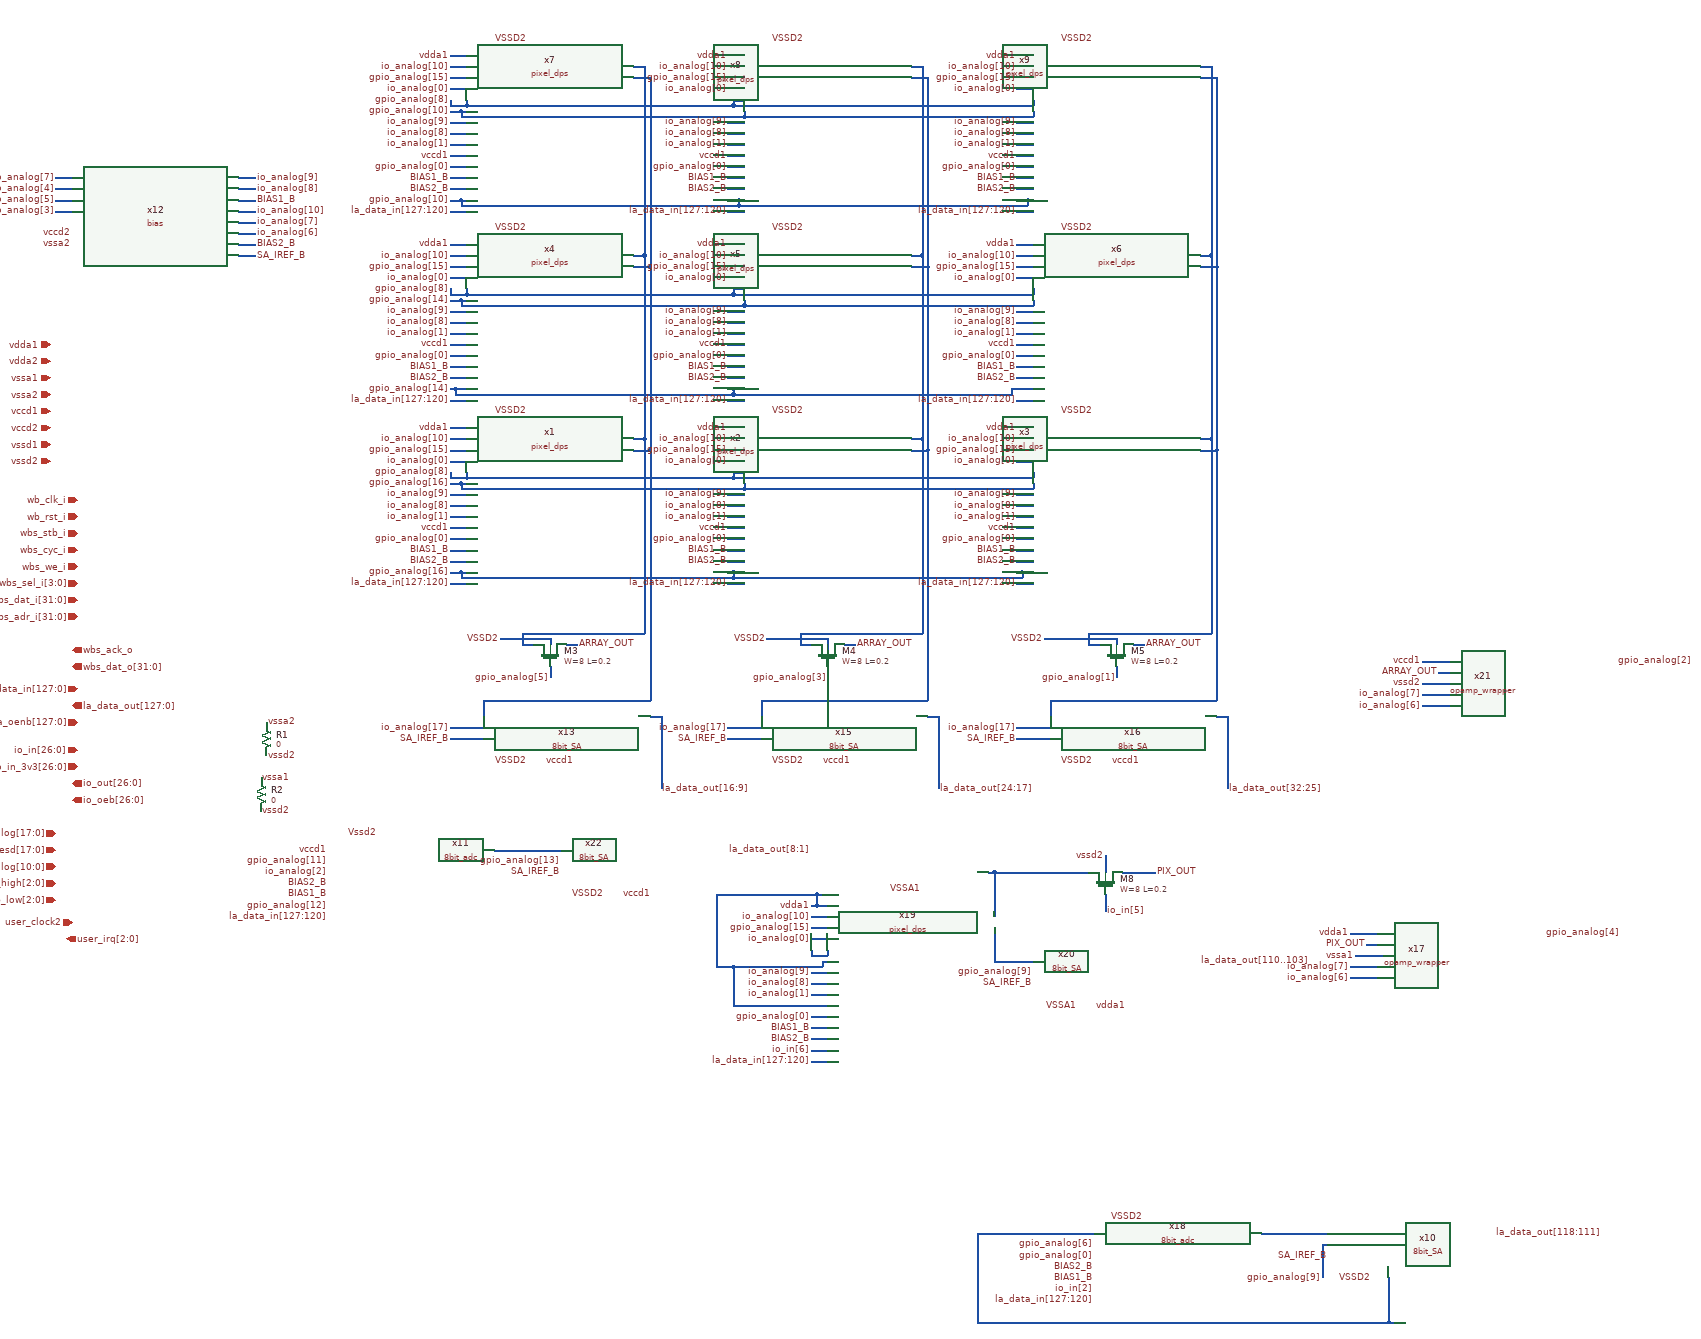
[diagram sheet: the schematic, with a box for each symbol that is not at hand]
v {xschem version=3.1.0 file_version=1.2
}
G {}
K {}
V {}
S {}
E {}
N 4290 -970 4310 -970 {
lab=#net1}
N 4310 -300 4310 50 {
lab=#net1}
N 4290 -300 4310 -300 {
lab=#net1}
N 4290 -630 4310 -630 {
lab=#net1}
N 4020 170 4320 170 {
lab=#net2}
N 4020 170 4020 200 {
lab=#net2}
N 3960 220 4020 220 {
lab=io_analog[17]}
N 3960 240 4020 240 {
lab=SA_IREF_B}
N 4320 200 4340 200 {
lab=la_data_in[16:9]}
N 4340 200 4340 330 {
lab=la_data_in[16:9]}
N 4090 50 4310 50 {
lab=#net1}
N 4090 50 4090 70 {
lab=#net1}
N 4090 70 4110 70 {
lab=#net1}
N 4170 70 4190 70 {
lab=ARRAY_OUT}
N 4140 110 4140 130 {
lab=gpio_analog[5]}
N 3580 -650 3610 -650 {
lab=BIAS2_B}
N 3580 -630 3610 -630 {
lab=SA_IREF_B}
N 3580 -670 3610 -670 {
lab=io_analog[6]}
N 3580 -730 3610 -730 {
lab=BIAS1_B}
N 3580 -710 3610 -710 {
lab=io_analog[10]}
N 3580 -690 3610 -690 {
lab=io_analog[7]}
N 3580 -750 3610 -750 {
lab=io_analog[8]}
N 3580 -770 3610 -770 {
lab=io_analog[9]}
N 3250 -770 3280 -770 {
lab=gpio_analog[7]}
N 3250 -750 3280 -750 {
lab=io_analog[4]}
N 3250 -730 3280 -730 {
lab=io_analog[5]}
N 3250 -710 3280 -710 {
lab=io_analog[3]}
N 3960 -870 3990 -870 {
lab=io_analog[9]}
N 3960 -850 3990 -850 {
lab=io_analog[8]}
N 3960 -750 3990 -750 {
lab=BIAS2_B}
N 3960 -770 3990 -770 {
lab=BIAS1_B}
N 3960 -970 3990 -970 {
lab=io_analog[10]}
N 3960 -950 3990 -950 {
lab=gpio_analog[15]}
N 3960 -930 3990 -930 {
lab=io_analog[0]}
N 3980 -890 3990 -890 {
lab=gpio_analog[10]}
N 3960 -830 3990 -830 {
lab=io_analog[1]}
N 3960 -810 3990 -810 {
lab=vccd1}
N 3960 -790 3990 -790 {
lab=gpio_analog[0]}
N 3980 -730 3990 -730 {
lab=gpio_analog[10]}
N 3960 -710 3990 -710 {
lab=la_data_in[127:120]}
N 3960 -530 3990 -530 {
lab=io_analog[9]}
N 3960 -510 3990 -510 {
lab=io_analog[8]}
N 3960 -410 3990 -410 {
lab=BIAS2_B}
N 3960 -430 3990 -430 {
lab=BIAS1_B}
N 3960 -630 3990 -630 {
lab=io_analog[10]}
N 3960 -610 3990 -610 {
lab=gpio_analog[15]}
N 3960 -590 3990 -590 {
lab=io_analog[0]}
N 3960 -490 3990 -490 {
lab=io_analog[1]}
N 3960 -470 3990 -470 {
lab=vccd1}
N 3960 -450 3990 -450 {
lab=gpio_analog[0]}
N 3970 -390 3990 -390 {
lab=gpio_analog[14]}
N 3960 -370 3990 -370 {
lab=la_data_in[127:120]}
N 3960 -200 3990 -200 {
lab=io_analog[9]}
N 3960 -180 3990 -180 {
lab=io_analog[8]}
N 3960 -80 3990 -80 {
lab=BIAS2_B}
N 3960 -100 3990 -100 {
lab=BIAS1_B}
N 3960 -300 3990 -300 {
lab=io_analog[10]}
N 3960 -280 3990 -280 {
lab=gpio_analog[15]}
N 3960 -260 3990 -260 {
lab=io_analog[0]}
N 3960 -160 3990 -160 {
lab=io_analog[1]}
N 3960 -140 3990 -140 {
lab=vccd1}
N 3960 -120 3990 -120 {
lab=gpio_analog[0]}
N 3980 -60 3990 -60 {
lab=gpio_analog[16]}
N 3960 -40 3990 -40 {
lab=la_data_in[127:120]}
N 4460 -870 4490 -870 {
lab=io_analog[9]}
N 4460 -850 4490 -850 {
lab=io_analog[8]}
N 4460 -750 4490 -750 {
lab=BIAS2_B}
N 4460 -770 4490 -770 {
lab=BIAS1_B}
N 4460 -970 4490 -970 {
lab=io_analog[10]}
N 4460 -950 4490 -950 {
lab=gpio_analog[15]}
N 4460 -930 4490 -930 {
lab=io_analog[0]}
N 4460 -830 4490 -830 {
lab=io_analog[1]}
N 4460 -810 4490 -810 {
lab=vccd1}
N 4460 -790 4490 -790 {
lab=gpio_analog[0]}
N 4480 -730 4490 -730 {
lab=gpio_analog[10]}
N 4460 -710 4490 -710 {
lab=la_data_in[127:120]}
N 4460 -530 4490 -530 {
lab=io_analog[9]}
N 4460 -510 4490 -510 {
lab=io_analog[8]}
N 4460 -410 4490 -410 {
lab=BIAS2_B}
N 4460 -430 4490 -430 {
lab=BIAS1_B}
N 4460 -630 4490 -630 {
lab=io_analog[10]}
N 4460 -610 4490 -610 {
lab=gpio_analog[15]}
N 4460 -590 4490 -590 {
lab=io_analog[0]}
N 4460 -490 4490 -490 {
lab=io_analog[1]}
N 4460 -470 4490 -470 {
lab=vccd1}
N 4460 -450 4490 -450 {
lab=gpio_analog[0]}
N 4470 -390 4490 -390 {
lab=gpio_analog[14]}
N 4460 -370 4490 -370 {
lab=la_data_in[127:120]}
N 4460 -200 4490 -200 {
lab=io_analog[9]}
N 4460 -180 4490 -180 {
lab=io_analog[8]}
N 4460 -80 4490 -80 {
lab=BIAS2_B}
N 4460 -100 4490 -100 {
lab=BIAS1_B}
N 4460 -300 4490 -300 {
lab=io_analog[10]}
N 4460 -280 4490 -280 {
lab=gpio_analog[15]}
N 4460 -260 4490 -260 {
lab=io_analog[0]}
N 4460 -160 4490 -160 {
lab=io_analog[1]}
N 4460 -140 4490 -140 {
lab=vccd1}
N 4460 -120 4490 -120 {
lab=gpio_analog[0]}
N 4470 -60 4490 -60 {
lab=gpio_analog[16]}
N 4460 -40 4490 -40 {
lab=la_data_in[127:120]}
N 4790 -970 4810 -970 {
lab=#net3}
N 4810 -300 4810 50 {
lab=#net3}
N 4790 -300 4810 -300 {
lab=#net3}
N 4790 -630 4810 -630 {
lab=#net3}
N 4980 -870 5010 -870 {
lab=io_analog[9]}
N 4980 -850 5010 -850 {
lab=io_analog[8]}
N 4980 -750 5010 -750 {
lab=BIAS2_B}
N 4980 -770 5010 -770 {
lab=BIAS1_B}
N 4980 -970 5010 -970 {
lab=io_analog[10]}
N 4980 -950 5010 -950 {
lab=gpio_analog[15]}
N 4980 -930 5010 -930 {
lab=io_analog[0]}
N 4980 -830 5010 -830 {
lab=io_analog[1]}
N 4980 -810 5010 -810 {
lab=vccd1}
N 4980 -790 5010 -790 {
lab=gpio_analog[0]}
N 5000 -730 5010 -730 {
lab=gpio_analog[10]}
N 4980 -710 5010 -710 {
lab=la_data_in[127:120]}
N 4980 -530 5010 -530 {
lab=io_analog[9]}
N 4980 -510 5010 -510 {
lab=io_analog[8]}
N 4980 -410 5010 -410 {
lab=BIAS2_B}
N 4980 -430 5010 -430 {
lab=BIAS1_B}
N 4980 -630 5010 -630 {
lab=io_analog[10]}
N 4980 -610 5010 -610 {
lab=gpio_analog[15]}
N 4980 -590 5010 -590 {
lab=io_analog[0]}
N 4980 -490 5010 -490 {
lab=io_analog[1]}
N 4980 -470 5010 -470 {
lab=vccd1}
N 4980 -450 5010 -450 {
lab=gpio_analog[0]}
N 4980 -370 5010 -370 {
lab=la_data_in[127:120]}
N 4980 -200 5010 -200 {
lab=io_analog[9]}
N 4980 -180 5010 -180 {
lab=io_analog[8]}
N 4980 -80 5010 -80 {
lab=BIAS2_B}
N 4980 -100 5010 -100 {
lab=BIAS1_B}
N 4980 -300 5010 -300 {
lab=io_analog[10]}
N 4980 -280 5010 -280 {
lab=gpio_analog[15]}
N 4980 -260 5010 -260 {
lab=io_analog[0]}
N 4980 -160 5010 -160 {
lab=io_analog[1]}
N 4980 -140 5010 -140 {
lab=vccd1}
N 4980 -120 5010 -120 {
lab=gpio_analog[0]}
N 4990 -60 5010 -60 {
lab=gpio_analog[16]}
N 4980 -40 5010 -40 {
lab=la_data_in[127:120]}
N 5310 -970 5330 -970 {
lab=#net4}
N 5330 -300 5330 50 {
lab=#net4}
N 5310 -300 5330 -300 {
lab=#net4}
N 5310 -630 5330 -630 {
lab=#net4}
N 4520 170 4820 170 {
lab=#net5}
N 4520 170 4520 200 {
lab=#net5}
N 4460 220 4520 220 {
lab=io_analog[17]}
N 4460 240 4520 240 {
lab=SA_IREF_B}
N 4820 200 4840 200 {
lab=la_data_in[24:17]}
N 4840 200 4840 330 {
lab=la_data_in[24:17]}
N 4590 50 4810 50 {
lab=#net3}
N 4590 50 4590 70 {
lab=#net3}
N 4590 70 4610 70 {
lab=#net3}
N 4670 70 4690 70 {
lab=ARRAY_OUT}
N 4640 110 4640 130 {
lab=gpio_analog[3]}
N 5040 170 5340 170 {
lab=#net6}
N 5040 170 5040 200 {
lab=#net6}
N 4980 220 5040 220 {
lab=io_analog[17]}
N 4980 240 5040 240 {
lab=SA_IREF_B}
N 5340 200 5360 200 {
lab=la_data_in[32:25]}
N 5360 200 5360 330 {
lab=la_data_in[32:25]}
N 5110 50 5330 50 {
lab=#net4}
N 5110 50 5110 70 {
lab=#net4}
N 5110 70 5130 70 {
lab=#net4}
N 5190 70 5210 70 {
lab=ARRAY_OUT}
N 5160 110 5160 130 {
lab=gpio_analog[1]}
N 4140 60 4140 70 {
lab=VSSD2}
N 4050 60 4140 60 {
lab=VSSD2}
N 4640 60 4640 80 {
lab=VSSD2}
N 4530 60 4640 60 {
lab=VSSD2}
N 5160 60 5160 70 {
lab=VSSD2}
N 5030 60 5160 60 {
lab=VSSD2}
N 4310 -630 4310 -300 {
lab=#net1}
N 4310 -970 4310 -630 {
lab=#net1}
N 4320 -610 4320 -280 {
lab=#net2}
N 4810 -630 4810 -300 {
lab=#net3}
N 4810 -970 4810 -630 {
lab=#net3}
N 4820 -610 4820 -280 {
lab=#net5}
N 5330 -630 5330 -300 {
lab=#net4}
N 5330 -970 5330 -630 {
lab=#net4}
N 5340 -610 5340 -280 {
lab=#net6}
N 4470 -910 4490 -910 {
lab=gpio_analog[8]}
N 4470 -910 4470 -900 {
lab=gpio_analog[8]}
N 3990 -900 4470 -900 {
lab=gpio_analog[8]}
N 3960 -910 3960 -900 {
lab=gpio_analog[8]}
N 3990 -910 3990 -900 {
lab=gpio_analog[8]}
N 4470 -900 5010 -900 {
lab=gpio_analog[8]}
N 5010 -910 5010 -900 {
lab=gpio_analog[8]}
N 4470 -570 4490 -570 {
lab=gpio_analog[8]}
N 4470 -570 4470 -560 {
lab=gpio_analog[8]}
N 3990 -560 4470 -560 {
lab=gpio_analog[8]}
N 3990 -570 3990 -560 {
lab=gpio_analog[8]}
N 4470 -560 5010 -560 {
lab=gpio_analog[8]}
N 5010 -570 5010 -560 {
lab=gpio_analog[8]}
N 3960 -570 3960 -560 {
lab=gpio_analog[8]}
N 4470 -240 4490 -240 {
lab=gpio_analog[8]}
N 4470 -240 4470 -230 {
lab=gpio_analog[8]}
N 3990 -230 4470 -230 {
lab=gpio_analog[8]}
N 3990 -240 3990 -230 {
lab=gpio_analog[8]}
N 4470 -230 5010 -230 {
lab=gpio_analog[8]}
N 5010 -240 5010 -230 {
lab=gpio_analog[8]}
N 3960 -240 3960 -230 {
lab=gpio_analog[8]}
N 4320 -950 4320 -610 {
lab=#net2}
N 4290 -950 4320 -950 {
lab=#net2}
N 4290 -610 4320 -610 {
lab=#net2}
N 4290 -280 4320 -280 {
lab=#net2}
N 4790 -610 4820 -610 {
lab=#net5}
N 4820 -950 4820 -610 {
lab=#net5}
N 4790 -950 4820 -950 {
lab=#net5}
N 4790 -280 4820 -280 {
lab=#net5}
N 5310 -950 5340 -950 {
lab=#net6}
N 5310 -610 5340 -610 {
lab=#net6}
N 5310 -280 5340 -280 {
lab=#net6}
N 4320 -280 4320 170 {
lab=#net2}
N 4820 -280 4820 170 {
lab=#net5}
N 5340 -280 5340 170 {
lab=#net6}
N 5340 -950 5340 -610 {
lab=#net6}
N 3960 -900 3990 -900 {
lab=gpio_analog[8]}
N 3960 -560 3990 -560 {
lab=gpio_analog[8]}
N 3960 -230 3990 -230 {
lab=gpio_analog[8]}
N 3980 -890 3980 -880 {
lab=gpio_analog[10]}
N 3980 -880 4490 -880 {
lab=gpio_analog[10]}
N 4490 -890 4490 -880 {
lab=gpio_analog[10]}
N 4490 -880 5010 -880 {
lab=gpio_analog[10]}
N 5010 -890 5010 -880 {
lab=gpio_analog[10]}
N 3960 -890 3980 -890 {
lab=gpio_analog[10]}
N 3980 -550 3990 -550 {
lab=gpio_analog[14]}
N 3980 -550 3980 -540 {
lab=gpio_analog[14]}
N 3980 -540 4490 -540 {
lab=gpio_analog[14]}
N 4490 -550 4490 -540 {
lab=gpio_analog[14]}
N 4490 -540 5010 -540 {
lab=gpio_analog[14]}
N 5010 -550 5010 -540 {
lab=gpio_analog[14]}
N 3960 -550 3980 -550 {
lab=gpio_analog[14]}
N 3980 -220 3990 -220 {
lab=gpio_analog[16]}
N 3980 -220 3980 -210 {
lab=gpio_analog[16]}
N 3980 -210 4490 -210 {
lab=gpio_analog[16]}
N 4490 -220 4490 -210 {
lab=gpio_analog[16]}
N 4490 -210 5010 -210 {
lab=gpio_analog[16]}
N 5010 -220 5010 -210 {
lab=gpio_analog[16]}
N 3960 -220 3980 -220 {
lab=gpio_analog[16]}
N 5140 520 5140 550 {
lab=io_in[5]}
N 5140 450 5140 480 {
lab=vssd2}
N 4940 480 5110 480 {
lab=#net7}
N 4940 480 4940 560 {
lab=#net7}
N 5170 480 5230 480 {
lab=PIX_OUT}
N 4940 580 4940 640 {
lab=#net8}
N 4940 640 5010 640 {
lab=#net8}
N 3960 -320 3990 -320 {
lab=vdda1}
N 3960 -650 3990 -650 {
lab=vdda1}
N 3960 -990 3990 -990 {
lab=vdda1}
N 4460 -990 4490 -990 {
lab=vdda1}
N 4980 -990 5010 -990 {
lab=vdda1}
N 4980 -650 5010 -650 {
lab=vdda1}
N 4460 -650 4490 -650 {
lab=vdda1}
N 4460 -320 4490 -320 {
lab=vdda1}
N 4980 -320 5010 -320 {
lab=vdda1}
N 4610 660 4640 660 {
lab=io_analog[9]}
N 4610 680 4640 680 {
lab=io_analog[8]}
N 4610 780 4640 780 {
lab=BIAS2_B}
N 4610 760 4640 760 {
lab=BIAS1_B}
N 4610 560 4640 560 {
lab=io_analog[10]}
N 4610 580 4640 580 {
lab=gpio_analog[15]}
N 4610 600 4640 600 {
lab=io_analog[0]}
N 4610 700 4640 700 {
lab=io_analog[1]}
N 4610 740 4640 740 {
lab=gpio_analog[0]}
N 4610 800 4640 800 {
lab=io_in[6]}
N 4610 820 4640 820 {
lab=la_data_in[127:120]}
N 4640 620 4640 630 {
lab=#net9}
N 4610 620 4610 630 {
lab=#net9}
N 4610 630 4640 630 {
lab=#net9}
N 4630 640 4640 640 {
lab=vdda1}
N 4630 640 4630 650 {
lab=vdda1}
N 4620 540 4640 540 {
lab=vdda1}
N 4040 440 4160 440 {
lab=#net10}
N 5420 1130 5540 1130 {
lab=#net11}
N 4470 650 4630 650 {
lab=vdda1}
N 5530 1150 5530 1210 {
lab=gpio_analog[9]}
N 5530 1150 5540 1150 {
lab=gpio_analog[9]}
N 4620 520 4630 520 {
lab=vdda1}
N 4930 480 4940 480 {
lab=#net7}
N 4440 520 4440 650 {
lab=vdda1}
N 4610 540 4620 540 {
lab=vdda1}
N 3980 -60 3980 -50 {
lab=gpio_analog[16]}
N 3980 -50 4470 -50 {
lab=gpio_analog[16]}
N 4470 -60 4470 -50 {
lab=gpio_analog[16]}
N 4470 -50 4990 -50 {
lab=gpio_analog[16]}
N 4990 -60 4990 -50 {
lab=gpio_analog[16]}
N 4470 720 4640 720 {
lab=vdda1}
N 4470 650 4470 720 {
lab=vdda1}
N 3970 -390 3970 -380 {
lab=gpio_analog[14]}
N 3970 -380 4470 -380 {
lab=gpio_analog[14]}
N 4470 -390 4470 -380 {
lab=gpio_analog[14]}
N 4470 -380 4970 -380 {
lab=gpio_analog[14]}
N 4970 -390 5010 -390 {
lab=gpio_analog[14]}
N 4970 -390 4970 -380 {
lab=gpio_analog[14]}
N 3980 -730 3980 -720 {
lab=gpio_analog[10]}
N 3980 -720 4480 -720 {
lab=gpio_analog[10]}
N 4480 -730 4480 -720 {
lab=gpio_analog[10]}
N 4480 -720 5000 -720 {
lab=gpio_analog[10]}
N 5000 -730 5000 -720 {
lab=gpio_analog[10]}
N 3960 -60 3980 -60 {
lab=gpio_analog[16]}
N 4460 -60 4470 -60 {
lab=gpio_analog[16]}
N 4980 -60 4990 -60 {
lab=gpio_analog[16]}
N 4440 650 4470 650 {
lab=vdda1}
N 3960 -390 3970 -390 {
lab=gpio_analog[14]}
N 4460 -390 4470 -390 {
lab=gpio_analog[14]}
N 3960 -730 3980 -730 {
lab=gpio_analog[10]}
N 4460 -730 4480 -730 {
lab=gpio_analog[10]}
N 4980 -730 5000 -730 {
lab=gpio_analog[10]}
N 4620 520 4620 540 {
lab=vdda1}
N 5650 1290 5660 1290 {
lab=#net12}
N 5650 1210 5650 1290 {
lab=#net12}
N 4910 1130 5120 1130 {
lab=#net12}
N 4440 520 4620 520 {
lab=vdda1}
N 4910 1130 4910 1290 {
lab=#net12}
N 4910 1290 5650 1290 {
lab=#net12}
N 5580 590 5630 590 {
lab=vdda1}
N 5590 630 5640 630 {
lab=vssa1}
N 5610 610 5630 610 {
lab=PIX_OUT}
N 5580 670 5630 670 {
lab=io_analog[6]}
N 5580 650 5630 650 {
lab=io_analog[7]}
N 5740 120 5760 120 {
lab=ARRAY_OUT}
N 5710 100 5760 100 {
lab=vccd1}
N 5710 140 5760 140 {
lab=vssd2}
N 5710 160 5760 160 {
lab=io_analog[7]}
N 5710 180 5760 180 {
lab=io_analog[6]}
C {devices/iopin.sym} 3240 -470 0 0 {name=p1 lab=vdda1}
C {devices/iopin.sym} 3240 -440 0 0 {name=p2 lab=vdda2}
C {devices/iopin.sym} 3240 -410 0 0 {name=p3 lab=vssa1}
C {devices/iopin.sym} 3240 -380 0 0 {name=p4 lab=vssa2}
C {devices/iopin.sym} 3240 -350 0 0 {name=p5 lab=vccd1}
C {devices/iopin.sym} 3240 -320 0 0 {name=p6 lab=vccd2}
C {devices/iopin.sym} 3240 -290 0 0 {name=p7 lab=vssd1}
C {devices/iopin.sym} 3240 -260 0 0 {name=p8 lab=vssd2}
C {devices/ipin.sym} 3290 -190 0 0 {name=p9 lab=wb_clk_i}
C {devices/ipin.sym} 3290 -160 0 0 {name=p10 lab=wb_rst_i}
C {devices/ipin.sym} 3290 -130 0 0 {name=p11 lab=wbs_stb_i}
C {devices/ipin.sym} 3290 -100 0 0 {name=p12 lab=wbs_cyc_i}
C {devices/ipin.sym} 3290 -70 0 0 {name=p13 lab=wbs_we_i}
C {devices/ipin.sym} 3290 -40 0 0 {name=p14 lab=wbs_sel_i[3:0]}
C {devices/ipin.sym} 3290 -10 0 0 {name=p15 lab=wbs_dat_i[31:0]}
C {devices/ipin.sym} 3290 20 0 0 {name=p16 lab=wbs_adr_i[31:0]}
C {devices/opin.sym} 3280 80 0 0 {name=p17 lab=wbs_ack_o}
C {devices/opin.sym} 3280 110 0 0 {name=p18 lab=wbs_dat_o[31:0]}
C {devices/ipin.sym} 3290 150 0 0 {name=p19 lab=la_data_in[127:0]}
C {devices/opin.sym} 3280 180 0 0 {name=p20 lab=la_data_out[127:0]}
C {devices/ipin.sym} 3290 260 0 0 {name=p21 lab=io_in[26:0]}
C {devices/ipin.sym} 3290 290 0 0 {name=p22 lab=io_in_3v3[26:0]}
C {devices/ipin.sym} 3280 570 0 0 {name=p23 lab=user_clock2}
C {devices/opin.sym} 3280 320 0 0 {name=p24 lab=io_out[26:0]}
C {devices/opin.sym} 3280 350 0 0 {name=p25 lab=io_oeb[26:0]}
C {devices/iopin.sym} 3250 410 0 0 {name=p26 lab=gpio_analog[17:0]}
C {devices/iopin.sym} 3250 440 0 0 {name=p27 lab=gpio_noesd[17:0]}
C {devices/iopin.sym} 3250 470 0 0 {name=p29 lab=io_analog[10:0]}
C {devices/iopin.sym} 3250 500 0 0 {name=p30 lab=io_clamp_high[2:0]}
C {devices/iopin.sym} 3250 530 0 0 {name=p31 lab=io_clamp_low[2:0]}
C {devices/opin.sym} 3270 600 0 0 {name=p32 lab=user_irq[2:0]}
C {devices/ipin.sym} 3290 210 0 0 {name=p28 lab=la_oenb[127:0]}
C {pixel_dps.sym} 4140 -180 0 0 {name=x1}
C {pixel_dps.sym} 4640 -180 0 0 {name=x2}
C {pixel_dps.sym} 4140 -510 0 0 {name=x4}
C {pixel_dps.sym} 4640 -510 0 0 {name=x5}
C {pixel_dps.sym} 4140 -850 0 0 {name=x7}
C {pixel_dps.sym} 4640 -850 0 0 {name=x8}
C {bias.sym} 3430 -700 0 0 {name=x12}
C {8bit_SA.sym} 4170 220 0 0 {name=x13}
C {sky130_fd_pr/nfet_01v8_lvt.sym} 4140 90 3 0 {name=M3
L=0.2
W=8
nf=1
mult=1
ad="'int((nf+1)/2) * W/nf * 0.29'" 
pd="'2*int((nf+1)/2) * (W/nf + 0.29)'"
as="'int((nf+2)/2) * W/nf * 0.29'" 
ps="'2*int((nf+2)/2) * (W/nf + 0.29)'"
nrd="'0.29 / W'" nrs="'0.29 / W'"
sa=0 sb=0 sd=0
model=nfet_01v8_lvt
spiceprefix=X
}
C {devices/lab_pin.sym} 3610 -630 2 0 {name=l11 sig_type=std_logic lab=SA_IREF_B}
C {devices/lab_pin.sym} 3960 240 0 0 {name=l12 sig_type=std_logic lab=SA_IREF_B}
C {devices/lab_pin.sym} 4140 130 0 0 {name=l34 sig_type=std_logic lab=gpio_analog[5]}
C {devices/lab_pin.sym} 4190 70 2 0 {name=l35 sig_type=std_logic lab=ARRAY_OUT}
C {devices/lab_pin.sym} 3610 -650 2 0 {name=l38 sig_type=std_logic lab=BIAS2_B}
C {devices/lab_pin.sym} 3610 -730 2 0 {name=l39 sig_type=std_logic lab=BIAS1_B}
C {devices/lab_pin.sym} 3610 -710 2 0 {name=l40 sig_type=std_logic lab=io_analog[10]}
C {devices/lab_pin.sym} 3610 -770 2 0 {name=l41 sig_type=std_logic lab=io_analog[9]}
C {devices/lab_pin.sym} 3610 -750 2 0 {name=l42 sig_type=std_logic lab=io_analog[8]}
C {devices/lab_pin.sym} 3250 -750 0 0 {name=l45 sig_type=std_logic lab=io_analog[4]}
C {devices/lab_pin.sym} 3960 -870 0 0 {name=l49 sig_type=std_logic lab=io_analog[9]}
C {devices/lab_pin.sym} 3960 -850 0 0 {name=l50 sig_type=std_logic lab=io_analog[8]}
C {devices/lab_pin.sym} 3960 -750 0 0 {name=l51 sig_type=std_logic lab=BIAS2_B}
C {devices/lab_pin.sym} 3960 -770 0 0 {name=l52 sig_type=std_logic lab=BIAS1_B}
C {devices/lab_pin.sym} 3960 -970 0 0 {name=l53 sig_type=std_logic lab=io_analog[10]}
C {devices/lab_pin.sym} 3960 -950 0 0 {name=l54 sig_type=std_logic lab=gpio_analog[15]}
C {devices/lab_pin.sym} 3960 -930 0 0 {name=l55 sig_type=std_logic lab=io_analog[0]}
C {devices/lab_pin.sym} 3960 -830 0 0 {name=l56 sig_type=std_logic lab=io_analog[1]}
C {devices/lab_pin.sym} 3960 -810 0 0 {name=l58 sig_type=std_logic lab=vccd1}
C {devices/lab_pin.sym} 3960 -790 0 0 {name=l59 sig_type=std_logic lab=gpio_analog[0]}
C {devices/lab_pin.sym} 3960 -730 0 0 {name=l60 sig_type=std_logic lab=gpio_analog[10]}
C {devices/lab_pin.sym} 3960 -710 0 0 {name=l61 sig_type=std_logic lab=la_data_in[127:120]}
C {devices/lab_pin.sym} 3960 -530 0 0 {name=l62 sig_type=std_logic lab=io_analog[9]}
C {devices/lab_pin.sym} 3960 -510 0 0 {name=l63 sig_type=std_logic lab=io_analog[8]}
C {devices/lab_pin.sym} 3960 -410 0 0 {name=l64 sig_type=std_logic lab=BIAS2_B}
C {devices/lab_pin.sym} 3960 -430 0 0 {name=l65 sig_type=std_logic lab=BIAS1_B}
C {devices/lab_pin.sym} 3960 -630 0 0 {name=l66 sig_type=std_logic lab=io_analog[10]}
C {devices/lab_pin.sym} 3960 -610 0 0 {name=l67 sig_type=std_logic lab=gpio_analog[15]}
C {devices/lab_pin.sym} 3960 -590 0 0 {name=l68 sig_type=std_logic lab=io_analog[0]}
C {devices/lab_pin.sym} 3960 -490 0 0 {name=l70 sig_type=std_logic lab=io_analog[1]}
C {devices/lab_pin.sym} 3960 -470 0 0 {name=l71 sig_type=std_logic lab=vccd1}
C {devices/lab_pin.sym} 3960 -450 0 0 {name=l72 sig_type=std_logic lab=gpio_analog[0]}
C {devices/lab_pin.sym} 3960 -370 0 0 {name=l74 sig_type=std_logic lab=la_data_in[127:120]}
C {devices/lab_pin.sym} 3960 -200 0 0 {name=l36 sig_type=std_logic lab=io_analog[9]}
C {devices/lab_pin.sym} 3960 -180 0 0 {name=l37 sig_type=std_logic lab=io_analog[8]}
C {devices/lab_pin.sym} 3960 -80 0 0 {name=l75 sig_type=std_logic lab=BIAS2_B}
C {devices/lab_pin.sym} 3960 -100 0 0 {name=l76 sig_type=std_logic lab=BIAS1_B}
C {devices/lab_pin.sym} 3960 -300 0 0 {name=l77 sig_type=std_logic lab=io_analog[10]}
C {devices/lab_pin.sym} 3960 -280 0 0 {name=l78 sig_type=std_logic lab=gpio_analog[15]}
C {devices/lab_pin.sym} 3960 -260 0 0 {name=l79 sig_type=std_logic lab=io_analog[0]}
C {devices/lab_pin.sym} 3960 -160 0 0 {name=l81 sig_type=std_logic lab=io_analog[1]}
C {devices/lab_pin.sym} 3960 -140 0 0 {name=l82 sig_type=std_logic lab=vccd1}
C {devices/lab_pin.sym} 3960 -120 0 0 {name=l83 sig_type=std_logic lab=gpio_analog[0]}
C {devices/lab_pin.sym} 3960 -40 0 0 {name=l85 sig_type=std_logic lab=la_data_in[127:120]}
C {devices/lab_pin.sym} 4460 -870 0 0 {name=l86 sig_type=std_logic lab=io_analog[9]}
C {devices/lab_pin.sym} 4460 -850 0 0 {name=l87 sig_type=std_logic lab=io_analog[8]}
C {devices/lab_pin.sym} 4460 -750 0 0 {name=l88 sig_type=std_logic lab=BIAS2_B}
C {devices/lab_pin.sym} 4460 -770 0 0 {name=l89 sig_type=std_logic lab=BIAS1_B}
C {devices/lab_pin.sym} 4460 -970 0 0 {name=l90 sig_type=std_logic lab=io_analog[10]}
C {devices/lab_pin.sym} 4460 -950 0 0 {name=l91 sig_type=std_logic lab=gpio_analog[15]}
C {devices/lab_pin.sym} 4460 -930 0 0 {name=l92 sig_type=std_logic lab=io_analog[0]}
C {devices/lab_pin.sym} 4460 -830 0 0 {name=l94 sig_type=std_logic lab=io_analog[1]}
C {devices/lab_pin.sym} 4460 -810 0 0 {name=l95 sig_type=std_logic lab=vccd1}
C {devices/lab_pin.sym} 4460 -790 0 0 {name=l96 sig_type=std_logic lab=gpio_analog[0]}
C {devices/lab_pin.sym} 4460 -710 0 0 {name=l98 sig_type=std_logic lab=la_data_in[127:120]}
C {devices/lab_pin.sym} 4460 -530 0 0 {name=l99 sig_type=std_logic lab=io_analog[9]}
C {devices/lab_pin.sym} 4460 -510 0 0 {name=l100 sig_type=std_logic lab=io_analog[8]}
C {devices/lab_pin.sym} 4460 -410 0 0 {name=l101 sig_type=std_logic lab=BIAS2_B}
C {devices/lab_pin.sym} 4460 -430 0 0 {name=l102 sig_type=std_logic lab=BIAS1_B}
C {devices/lab_pin.sym} 4460 -630 0 0 {name=l103 sig_type=std_logic lab=io_analog[10]}
C {devices/lab_pin.sym} 4460 -610 0 0 {name=l104 sig_type=std_logic lab=gpio_analog[15]}
C {devices/lab_pin.sym} 4460 -590 0 0 {name=l105 sig_type=std_logic lab=io_analog[0]}
C {devices/lab_pin.sym} 4460 -490 0 0 {name=l107 sig_type=std_logic lab=io_analog[1]}
C {devices/lab_pin.sym} 4460 -470 0 0 {name=l108 sig_type=std_logic lab=vccd1}
C {devices/lab_pin.sym} 4460 -450 0 0 {name=l109 sig_type=std_logic lab=gpio_analog[0]}
C {devices/lab_pin.sym} 4460 -370 0 0 {name=l111 sig_type=std_logic lab=la_data_in[127:120]}
C {devices/lab_pin.sym} 4460 -200 0 0 {name=l112 sig_type=std_logic lab=io_analog[9]}
C {devices/lab_pin.sym} 4460 -180 0 0 {name=l113 sig_type=std_logic lab=io_analog[8]}
C {devices/lab_pin.sym} 4460 -80 0 0 {name=l114 sig_type=std_logic lab=BIAS2_B}
C {devices/lab_pin.sym} 4460 -100 0 0 {name=l115 sig_type=std_logic lab=BIAS1_B}
C {devices/lab_pin.sym} 4460 -300 0 0 {name=l116 sig_type=std_logic lab=io_analog[10]}
C {devices/lab_pin.sym} 4460 -280 0 0 {name=l117 sig_type=std_logic lab=gpio_analog[15]}
C {devices/lab_pin.sym} 4460 -260 0 0 {name=l118 sig_type=std_logic lab=io_analog[0]}
C {devices/lab_pin.sym} 4460 -160 0 0 {name=l120 sig_type=std_logic lab=io_analog[1]}
C {devices/lab_pin.sym} 4460 -140 0 0 {name=l121 sig_type=std_logic lab=vccd1}
C {devices/lab_pin.sym} 4460 -120 0 0 {name=l122 sig_type=std_logic lab=gpio_analog[0]}
C {devices/lab_pin.sym} 4460 -40 0 0 {name=l124 sig_type=std_logic lab=la_data_in[127:120]}
C {pixel_dps.sym} 5160 -180 0 0 {name=x3}
C {pixel_dps.sym} 5160 -510 0 0 {name=x6}
C {pixel_dps.sym} 5160 -850 0 0 {name=x9}
C {devices/lab_pin.sym} 4980 -870 0 0 {name=l125 sig_type=std_logic lab=io_analog[9]}
C {devices/lab_pin.sym} 4980 -850 0 0 {name=l126 sig_type=std_logic lab=io_analog[8]}
C {devices/lab_pin.sym} 4980 -750 0 0 {name=l127 sig_type=std_logic lab=BIAS2_B}
C {devices/lab_pin.sym} 4980 -770 0 0 {name=l128 sig_type=std_logic lab=BIAS1_B}
C {devices/lab_pin.sym} 4980 -970 0 0 {name=l129 sig_type=std_logic lab=io_analog[10]}
C {devices/lab_pin.sym} 4980 -950 0 0 {name=l130 sig_type=std_logic lab=gpio_analog[15]}
C {devices/lab_pin.sym} 4980 -930 0 0 {name=l131 sig_type=std_logic lab=io_analog[0]}
C {devices/lab_pin.sym} 4980 -830 0 0 {name=l133 sig_type=std_logic lab=io_analog[1]}
C {devices/lab_pin.sym} 4980 -810 0 0 {name=l134 sig_type=std_logic lab=vccd1}
C {devices/lab_pin.sym} 4980 -790 0 0 {name=l135 sig_type=std_logic lab=gpio_analog[0]}
C {devices/lab_pin.sym} 4980 -710 0 0 {name=l137 sig_type=std_logic lab=la_data_in[127:120]}
C {devices/lab_pin.sym} 4980 -530 0 0 {name=l138 sig_type=std_logic lab=io_analog[9]}
C {devices/lab_pin.sym} 4980 -510 0 0 {name=l139 sig_type=std_logic lab=io_analog[8]}
C {devices/lab_pin.sym} 4980 -410 0 0 {name=l140 sig_type=std_logic lab=BIAS2_B}
C {devices/lab_pin.sym} 4980 -430 0 0 {name=l141 sig_type=std_logic lab=BIAS1_B}
C {devices/lab_pin.sym} 4980 -630 0 0 {name=l142 sig_type=std_logic lab=io_analog[10]}
C {devices/lab_pin.sym} 4980 -610 0 0 {name=l143 sig_type=std_logic lab=gpio_analog[15]}
C {devices/lab_pin.sym} 4980 -590 0 0 {name=l144 sig_type=std_logic lab=io_analog[0]}
C {devices/lab_pin.sym} 4980 -490 0 0 {name=l146 sig_type=std_logic lab=io_analog[1]}
C {devices/lab_pin.sym} 4980 -470 0 0 {name=l147 sig_type=std_logic lab=vccd1}
C {devices/lab_pin.sym} 4980 -450 0 0 {name=l148 sig_type=std_logic lab=gpio_analog[0]}
C {devices/lab_pin.sym} 4980 -370 0 0 {name=l150 sig_type=std_logic lab=la_data_in[127:120]}
C {devices/lab_pin.sym} 4980 -200 0 0 {name=l151 sig_type=std_logic lab=io_analog[9]}
C {devices/lab_pin.sym} 4980 -180 0 0 {name=l152 sig_type=std_logic lab=io_analog[8]}
C {devices/lab_pin.sym} 4980 -80 0 0 {name=l153 sig_type=std_logic lab=BIAS2_B}
C {devices/lab_pin.sym} 4980 -100 0 0 {name=l154 sig_type=std_logic lab=BIAS1_B}
C {devices/lab_pin.sym} 4980 -300 0 0 {name=l155 sig_type=std_logic lab=io_analog[10]}
C {devices/lab_pin.sym} 4980 -280 0 0 {name=l156 sig_type=std_logic lab=gpio_analog[15]}
C {devices/lab_pin.sym} 4980 -260 0 0 {name=l157 sig_type=std_logic lab=io_analog[0]}
C {devices/lab_pin.sym} 4980 -160 0 0 {name=l159 sig_type=std_logic lab=io_analog[1]}
C {devices/lab_pin.sym} 4980 -140 0 0 {name=l160 sig_type=std_logic lab=vccd1}
C {devices/lab_pin.sym} 4980 -120 0 0 {name=l161 sig_type=std_logic lab=gpio_analog[0]}
C {devices/lab_pin.sym} 4980 -40 0 0 {name=l163 sig_type=std_logic lab=la_data_in[127:120]}
C {8bit_SA.sym} 4670 220 0 0 {name=x15}
C {sky130_fd_pr/nfet_01v8_lvt.sym} 4640 90 3 0 {name=M4
L=0.2
W=8
nf=1
mult=1
ad="'int((nf+1)/2) * W/nf * 0.29'" 
pd="'2*int((nf+1)/2) * (W/nf + 0.29)'"
as="'int((nf+2)/2) * W/nf * 0.29'" 
ps="'2*int((nf+2)/2) * (W/nf + 0.29)'"
nrd="'0.29 / W'" nrs="'0.29 / W'"
sa=0 sb=0 sd=0
model=nfet_01v8_lvt
spiceprefix=X
}
C {devices/lab_pin.sym} 4460 240 0 0 {name=l164 sig_type=std_logic lab=SA_IREF_B}
C {devices/lab_pin.sym} 4640 130 0 0 {name=l166 sig_type=std_logic lab=gpio_analog[3]}
C {devices/lab_pin.sym} 4690 70 2 0 {name=l167 sig_type=std_logic lab=ARRAY_OUT}
C {8bit_SA.sym} 5190 220 0 0 {name=x16}
C {sky130_fd_pr/nfet_01v8_lvt.sym} 5160 90 3 0 {name=M5
L=0.2
W=8
nf=1
mult=1
ad="'int((nf+1)/2) * W/nf * 0.29'" 
pd="'2*int((nf+1)/2) * (W/nf + 0.29)'"
as="'int((nf+2)/2) * W/nf * 0.29'" 
ps="'2*int((nf+2)/2) * (W/nf + 0.29)'"
nrd="'0.29 / W'" nrs="'0.29 / W'"
sa=0 sb=0 sd=0
model=nfet_01v8_lvt
spiceprefix=X
}
C {devices/lab_pin.sym} 4980 240 0 0 {name=l168 sig_type=std_logic lab=SA_IREF_B}
C {devices/lab_pin.sym} 4980 220 0 0 {name=l169 sig_type=std_logic lab=io_analog[17]}
C {devices/lab_pin.sym} 5210 70 2 0 {name=l171 sig_type=std_logic lab=ARRAY_OUT}
C {devices/lab_pin.sym} 4050 60 0 0 {name=l15 sig_type=std_logic lab=VSSD2}
C {devices/lab_pin.sym} 4530 60 0 0 {name=l13 sig_type=std_logic lab=VSSD2}
C {devices/lab_pin.sym} 5030 60 0 0 {name=l14 sig_type=std_logic lab=VSSD2}
C {devices/lab_pin.sym} 4340 330 2 0 {name=l16 sig_type=std_logic lab=la_data_out[16:9]}
C {devices/lab_pin.sym} 4840 330 2 0 {name=l17 sig_type=std_logic lab=la_data_out[24:17]}
C {devices/lab_pin.sym} 5360 330 2 0 {name=l18 sig_type=std_logic lab=la_data_out[32:25]}
C {devices/lab_pin.sym} 3960 -910 0 0 {name=l22 sig_type=std_logic lab=gpio_analog[8]}
C {devices/lab_pin.sym} 3960 -570 0 0 {name=l19 sig_type=std_logic lab=gpio_analog[8]}
C {devices/lab_pin.sym} 3960 -240 0 0 {name=l20 sig_type=std_logic lab=gpio_analog[8]}
C {devices/lab_pin.sym} 3960 -890 0 0 {name=l21 sig_type=std_logic lab=gpio_analog[10]}
C {devices/lab_pin.sym} 3960 -550 0 0 {name=l23 sig_type=std_logic lab=gpio_analog[14]}
C {devices/lab_pin.sym} 3960 -220 0 0 {name=l24 sig_type=std_logic lab=gpio_analog[16]}
C {devices/lab_pin.sym} 3250 -730 0 0 {name=l25 sig_type=std_logic lab=io_analog[5]}
C {devices/lab_pin.sym} 3250 -710 0 0 {name=l26 sig_type=std_logic lab=io_analog[3]}
C {devices/lab_pin.sym} 3250 -770 0 0 {name=l27 sig_type=std_logic lab=gpio_analog[7]}
C {devices/lab_pin.sym} 3610 -690 2 0 {name=l28 sig_type=std_logic lab=io_analog[7]}
C {devices/lab_pin.sym} 3610 -670 2 0 {name=l29 sig_type=std_logic lab=io_analog[6]}
C {devices/lab_pin.sym} 5160 130 0 0 {name=l30 sig_type=std_logic lab=gpio_analog[1]}
C {adc/8bit_adc.sym} 3890 500 0 0 {name=x11}
C {adc/8bit_adc.sym} 5270 1190 0 0 {name=x18}
C {pixel_dps.sym} 4790 680 0 0 {name=x19}
C {8bit_SA.sym} 5160 660 0 0 {name=x20}
C {sky130_fd_pr/nfet_01v8_lvt.sym} 5140 500 3 0 {name=M8
L=0.2
W=8
nf=1
mult=1
ad="'int((nf+1)/2) * W/nf * 0.29'" 
pd="'2*int((nf+1)/2) * (W/nf + 0.29)'"
as="'int((nf+2)/2) * W/nf * 0.29'" 
ps="'2*int((nf+2)/2) * (W/nf + 0.29)'"
nrd="'0.29 / W'" nrs="'0.29 / W'"
sa=0 sb=0 sd=0
model=nfet_01v8_lvt
spiceprefix=X
}
C {devices/lab_pin.sym} 5140 550 2 0 {name=l80 sig_type=std_logic lab=io_in[5]}
C {devices/lab_pin.sym} 5140 450 1 0 {name=l93 sig_type=std_logic lab=vssd2}
C {devices/lab_pin.sym} 5230 480 2 0 {name=l44 sig_type=std_logic lab=PIX_OUT}
C {devices/lab_pin.sym} 5010 660 0 0 {name=l106 sig_type=std_logic lab=gpio_analog[9]}
C {devices/lab_pin.sym} 5010 680 0 0 {name=l119 sig_type=std_logic lab=SA_IREF_B}
C {devices/lab_pin.sym} 5310 640 2 0 {name=l132 sig_type=std_logic lab=la_data_out[110..103]}
C {devices/lab_pin.sym} 3960 -320 0 0 {name=l170 sig_type=std_logic lab=vdda1}
C {devices/lab_pin.sym} 3960 -990 0 0 {name=l173 sig_type=std_logic lab=vdda1}
C {devices/lab_pin.sym} 4610 660 0 0 {name=l180 sig_type=std_logic lab=io_analog[9]}
C {devices/lab_pin.sym} 4610 680 0 0 {name=l181 sig_type=std_logic lab=io_analog[8]}
C {devices/lab_pin.sym} 4610 780 0 0 {name=l182 sig_type=std_logic lab=BIAS2_B}
C {devices/lab_pin.sym} 4610 760 0 0 {name=l183 sig_type=std_logic lab=BIAS1_B}
C {devices/lab_pin.sym} 4610 560 0 0 {name=l184 sig_type=std_logic lab=io_analog[10]}
C {devices/lab_pin.sym} 4610 580 0 0 {name=l185 sig_type=std_logic lab=gpio_analog[15]}
C {devices/lab_pin.sym} 4610 600 0 0 {name=l186 sig_type=std_logic lab=io_analog[0]}
C {devices/lab_pin.sym} 4610 700 0 0 {name=l187 sig_type=std_logic lab=io_analog[1]}
C {devices/lab_pin.sym} 4610 740 0 0 {name=l189 sig_type=std_logic lab=gpio_analog[0]}
C {devices/lab_pin.sym} 4610 800 0 0 {name=l190 sig_type=std_logic lab=io_in[6]}
C {devices/lab_pin.sym} 4610 820 0 0 {name=l191 sig_type=std_logic lab=la_data_in[127:120]}
C {devices/lab_pin.sym} 4610 540 0 0 {name=l194 sig_type=std_logic lab=vdda1}
C {8bit_SA.sym} 4310 460 0 0 {name=x22}
C {devices/lab_pin.sym} 4160 460 0 0 {name=l195 sig_type=std_logic lab=gpio_analog[13]}
C {devices/lab_pin.sym} 4160 480 0 0 {name=l196 sig_type=std_logic lab=SA_IREF_B}
C {8bit_SA.sym} 5690 1150 0 0 {name=x10}
C {devices/lab_pin.sym} 5530 1210 0 0 {name=l197 sig_type=std_logic lab=gpio_analog[9]}
C {devices/lab_pin.sym} 5540 1170 0 0 {name=l198 sig_type=std_logic lab=SA_IREF_B}
C {devices/lab_pin.sym} 3740 440 0 0 {name=l199 sig_type=std_logic lab=vccd1}
C {devices/lab_pin.sym} 3740 460 0 0 {name=l200 sig_type=std_logic lab=gpio_analog[11]}
C {devices/lab_pin.sym} 3740 480 0 0 {name=l201 sig_type=std_logic lab=io_analog[2]}
C {devices/lab_pin.sym} 3740 560 0 0 {name=l202 sig_type=std_logic lab=la_data_in[127:120]}
C {devices/lab_pin.sym} 3740 500 0 0 {name=l203 sig_type=std_logic lab=BIAS2_B}
C {devices/lab_pin.sym} 3740 520 0 0 {name=l204 sig_type=std_logic lab=BIAS1_B}
C {devices/lab_pin.sym} 3740 540 0 0 {name=l205 sig_type=std_logic lab=gpio_analog[12]}
C {devices/lab_pin.sym} 4460 440 2 0 {name=l206 sig_type=std_logic lab=la_data_out[8:1]}
C {devices/lab_pin.sym} 5120 1150 0 0 {name=l208 sig_type=std_logic lab=gpio_analog[6]}
C {devices/lab_pin.sym} 5120 1170 0 0 {name=l209 sig_type=std_logic lab=gpio_analog[0]}
C {devices/lab_pin.sym} 5120 1250 0 0 {name=l210 sig_type=std_logic lab=la_data_in[127:120]}
C {devices/lab_pin.sym} 5120 1190 0 0 {name=l211 sig_type=std_logic lab=BIAS2_B}
C {devices/lab_pin.sym} 5120 1210 0 0 {name=l212 sig_type=std_logic lab=BIAS1_B}
C {devices/lab_pin.sym} 5120 1230 0 0 {name=l213 sig_type=std_logic lab=io_in[2]}
C {devices/lab_pin.sym} 5840 1130 2 0 {name=l214 sig_type=std_logic lab=la_data_out[118:111]}
C {devices/lab_pin.sym} 4100 -1020 0 0 {name=l193 sig_type=std_logic lab=VSSD2}
C {devices/lab_pin.sym} 4600 -1020 0 0 {name=l215 sig_type=std_logic lab=VSSD2}
C {devices/lab_pin.sym} 5120 -1020 0 0 {name=l216 sig_type=std_logic lab=VSSD2}
C {devices/lab_pin.sym} 4100 -680 0 0 {name=l217 sig_type=std_logic lab=VSSD2}
C {devices/lab_pin.sym} 4600 -680 0 0 {name=l218 sig_type=std_logic lab=VSSD2}
C {devices/lab_pin.sym} 5120 -680 0 0 {name=l219 sig_type=std_logic lab=VSSD2}
C {devices/lab_pin.sym} 4100 -350 0 0 {name=l220 sig_type=std_logic lab=VSSD2}
C {devices/lab_pin.sym} 4600 -350 0 0 {name=l221 sig_type=std_logic lab=VSSD2}
C {devices/lab_pin.sym} 5120 -350 0 0 {name=l222 sig_type=std_logic lab=VSSD2}
C {devices/lab_pin.sym} 4100 280 0 0 {name=l223 sig_type=std_logic lab=VSSD2}
C {devices/lab_pin.sym} 4130 280 2 0 {name=l224 sig_type=std_logic lab=vccd1}
C {devices/lab_pin.sym} 4600 280 0 0 {name=l225 sig_type=std_logic lab=VSSD2}
C {devices/lab_pin.sym} 4630 280 2 0 {name=l226 sig_type=std_logic lab=vccd1}
C {devices/lab_pin.sym} 5120 280 0 0 {name=l227 sig_type=std_logic lab=VSSD2}
C {devices/lab_pin.sym} 5150 280 2 0 {name=l228 sig_type=std_logic lab=vccd1}
C {devices/lab_pin.sym} 4750 510 2 0 {name=l229 sig_type=std_logic lab=VSSA1}
C {devices/lab_pin.sym} 4240 520 0 0 {name=l230 sig_type=std_logic lab=VSSD2}
C {devices/lab_pin.sym} 4270 520 2 0 {name=l231 sig_type=std_logic lab=vccd1}
C {devices/lab_pin.sym} 5620 1210 0 0 {name=l232 sig_type=std_logic lab=VSSD2}
C {devices/lab_pin.sym} 5120 720 2 0 {name=l235 sig_type=std_logic lab=vdda1}
C {devices/lab_pin.sym} 3830 410 0 0 {name=l236 sig_type=std_logic lab=Vssd2}
C {devices/lab_pin.sym} 5210 1100 0 0 {name=l237 sig_type=std_logic lab=VSSD2}
C {devices/lab_pin.sym} 5090 720 0 0 {name=l3 sig_type=std_logic lab=VSSA1}
C {devices/lab_pin.sym} 3280 -650 0 0 {name=l47 sig_type=std_logic lab=vssa2}
C {devices/lab_pin.sym} 3280 -670 0 0 {name=l192 sig_type=std_logic lab=vccd2}
C {devices/lab_pin.sym} 3960 -390 0 0 {name=l73 sig_type=std_logic lab=gpio_analog[14]}
C {devices/lab_pin.sym} 3960 -60 0 0 {name=l84 sig_type=std_logic lab=gpio_analog[16]}
C {devices/lab_pin.sym} 4460 220 0 0 {name=l33 sig_type=std_logic lab=io_analog[17]}
C {devices/lab_pin.sym} 3960 220 0 0 {name=l97 sig_type=std_logic lab=io_analog[17]}
C {devices/lab_pin.sym} 3960 -650 0 0 {name=l110 sig_type=std_logic lab=vdda1}
C {devices/lab_pin.sym} 4460 -990 0 0 {name=l123 sig_type=std_logic lab=vdda1}
C {devices/lab_pin.sym} 4460 -650 0 0 {name=l136 sig_type=std_logic lab=vdda1}
C {devices/lab_pin.sym} 4460 -320 0 0 {name=l149 sig_type=std_logic lab=vdda1}
C {devices/lab_pin.sym} 4980 -320 0 0 {name=l162 sig_type=std_logic lab=vdda1}
C {devices/lab_pin.sym} 4980 -650 0 0 {name=l165 sig_type=std_logic lab=vdda1}
C {devices/lab_pin.sym} 4980 -990 0 0 {name=l172 sig_type=std_logic lab=vdda1}
C {devices/res.sym} 3630 240 0 0 {name=R1
value=0
footprint=1206
device=resistor
m=1}
C {devices/lab_pin.sym} 3630 210 2 0 {name=l174 sig_type=std_logic lab=vssa2}
C {devices/lab_pin.sym} 3630 270 2 0 {name=l175 sig_type=std_logic lab=vssd2}
C {devices/res.sym} 3620 340 0 0 {name=R2
value=0
footprint=1206
device=resistor
m=1}
C {devices/lab_pin.sym} 3620 310 2 0 {name=l176 sig_type=std_logic lab=vssa1}
C {devices/lab_pin.sym} 3620 370 2 0 {name=l177 sig_type=std_logic lab=vssd2}
C {opamp_wrapper.sym} 5780 630 0 0 {name=x17}
C {devices/lab_pin.sym} 5580 590 0 0 {name=l178 sig_type=std_logic lab=vdda1}
C {devices/lab_pin.sym} 5930 590 2 0 {name=l179 sig_type=std_logic lab=gpio_analog[4]}
C {devices/lab_pin.sym} 5590 630 0 0 {name=l188 sig_type=std_logic lab=vssa1}
C {devices/lab_pin.sym} 5610 610 0 0 {name=l207 sig_type=std_logic lab=PIX_OUT}
C {devices/lab_pin.sym} 5580 670 0 0 {name=l233 sig_type=std_logic lab=io_analog[6]}
C {devices/lab_pin.sym} 5580 650 0 0 {name=l234 sig_type=std_logic lab=io_analog[7]}
C {opamp_wrapper.sym} 5910 140 0 0 {name=x21}
C {devices/lab_pin.sym} 5740 120 0 0 {name=l9 sig_type=std_logic lab=ARRAY_OUT}
C {devices/lab_pin.sym} 5710 100 0 0 {name=l31 sig_type=std_logic lab=vccd1}
C {devices/lab_pin.sym} 5710 140 0 0 {name=l32 sig_type=std_logic lab=vssd2}
C {devices/lab_pin.sym} 5710 160 0 0 {name=l43 sig_type=std_logic lab=io_analog[7]}
C {devices/lab_pin.sym} 5710 180 0 0 {name=l46 sig_type=std_logic lab=io_analog[6]}
C {devices/lab_pin.sym} 6060 100 2 0 {name=l48 sig_type=std_logic lab=gpio_analog[2]}
